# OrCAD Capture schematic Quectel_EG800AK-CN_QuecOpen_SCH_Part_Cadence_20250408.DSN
size A2

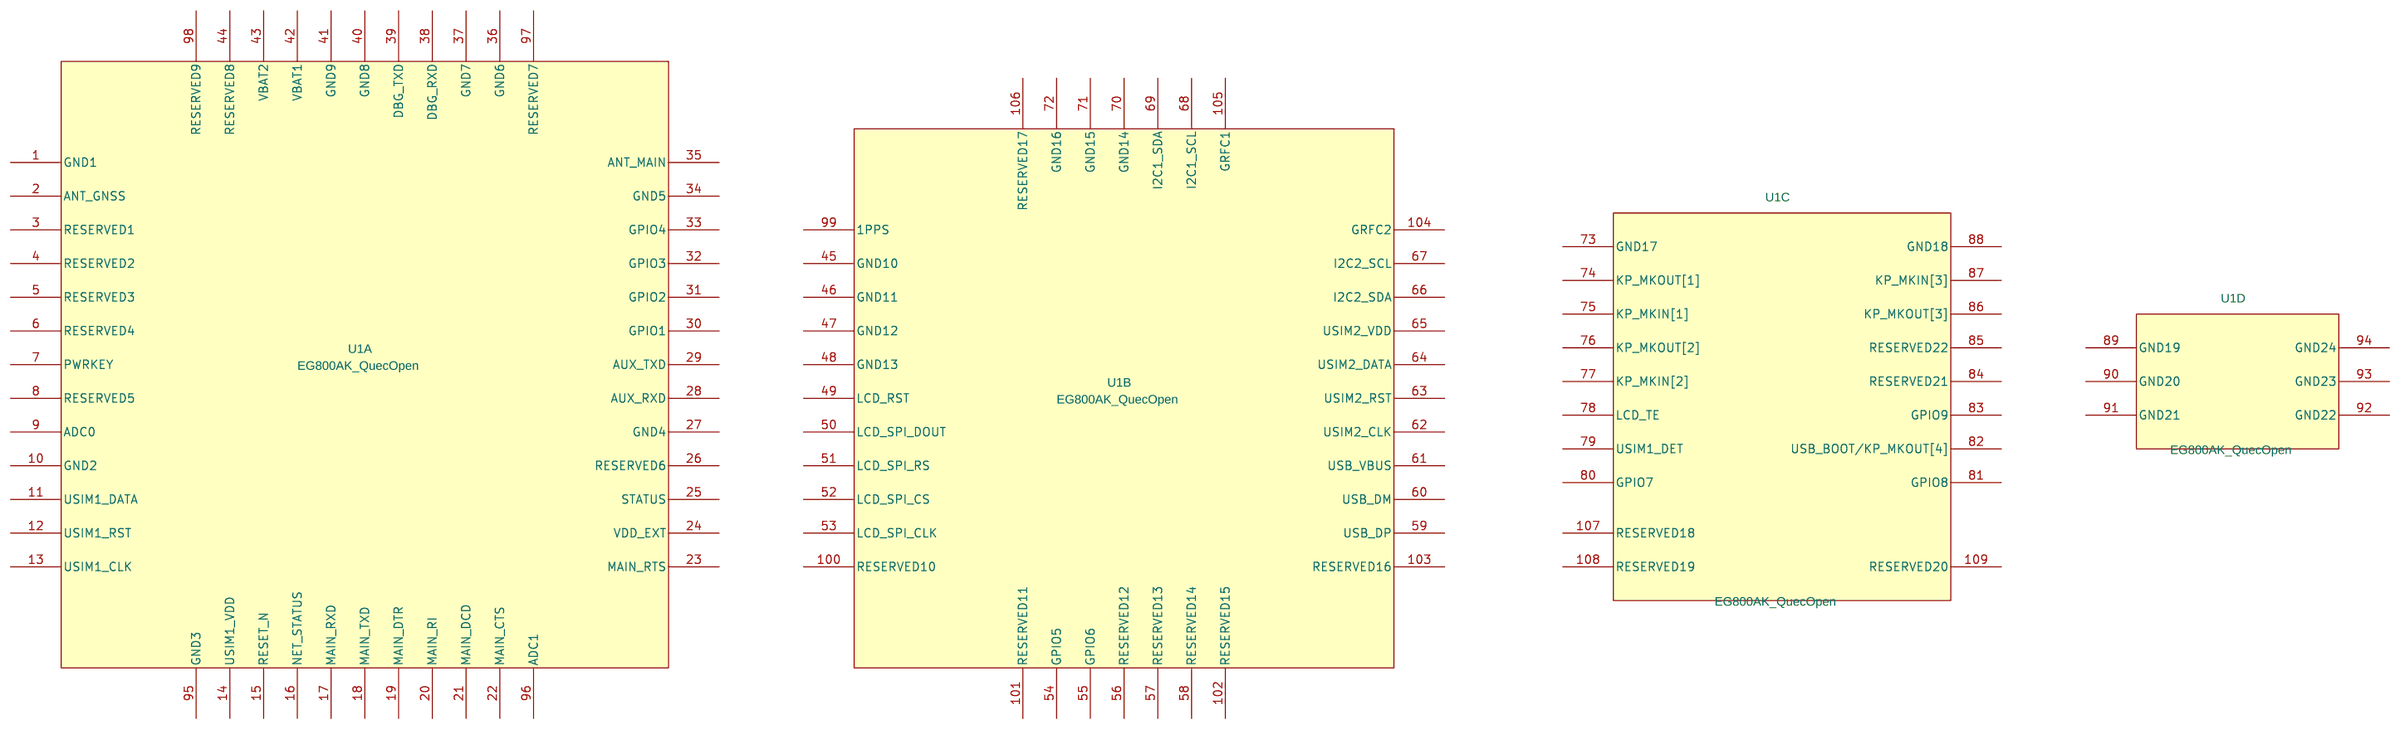
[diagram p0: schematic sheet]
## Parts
U1  EG800AK_QuecOpen  [EG800AK_QuecOpen]  (sections A,B,C,D)

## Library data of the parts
U1 = EG800AK_QuecOpen

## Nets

Not connected (* = marked no-connect by the designer): U1 1(GND1) 2(ANT_GNSS) 3(RESERVED1) 4(RESERVED2) 5(RESERVED3) 6(RESERVED4) 7(PWRKEY) 8(RESERVED5) 9(ADC0) 10(GND2) 11(USIM1_DATA) 12(USIM1_RST) 13(USIM1_CLK) 14(USIM1_VDD) 15(RESET_N) 16(NET_STATUS) 17(MAIN_RXD) 18(MAIN_TXD) 19(MAIN_DTR) 20(MAIN_RI) 21(MAIN_DCD) 22(MAIN_CTS) 23(MAIN_RTS) 24(VDD_EXT) 25(STATUS) 26(RESERVED6) 27(GND4) 28(AUX_RXD) 29(AUX_TXD) 30(GPIO1) 31(GPIO2) 32(GPIO3) 33(GPIO4) 34(GND5) 35(ANT_MAIN) 36(GND6) 37(GND7) 38(DBG_RXD) 39(DBG_TXD) 40(GND8) 41(GND9) 42(VBAT1) 43(VBAT2) 44(RESERVED8) 45(GND10) 46(GND11) 47(GND12) 48(GND13) 49(LCD_RST) 50(LCD_SPI_DOUT) 51(LCD_SPI_RS) 52(LCD_SPI_CS) 53(LCD_SPI_CLK) 54(GPIO5) 55(GPIO6) 56(RESERVED12) 57(RESERVED13) 58(RESERVED14) 59(USB_DP) 60(USB_DM) 61(USB_VBUS) 62(USIM2_CLK) 63(USIM2_RST) 64(USIM2_DATA) 65(USIM2_VDD) 66(I2C2_SDA) 67(I2C2_SCL) 68(I2C1_SCL) 69(I2C1_SDA) 70(GND14) 71(GND15) 72(GND16) 73(GND17) 74(KP_MKOUT[1]) 75(KP_MKIN[1]) 76(KP_MKOUT[2]) 77(KP_MKIN[2]) 78(LCD_TE) 79(USIM1_DET) 80(GPIO7) 81(GPIO8) 82(USB_BOOT/KP_MKOUT[4]) 83(GPIO9) 84(RESERVED21) 85(RESERVED22) 86(KP_MKOUT[3]) 87(KP_MKIN[3]) 88(GND18) 89(GND19) 90(GND20) 91(GND21) 92(GND22) 93(GND23) 94(GND24) 95(GND3) 96(ADC1) 97(RESERVED7) 98(RESERVED9) 99(1PPS) 100(RESERVED10) 101(RESERVED11) 102(RESERVED15) 103(RESERVED16) 104(GRFC2) 105(GRFC1) 106(RESERVED17) 107(RESERVED18) 108(RESERVED19) 109(RESERVED20)
